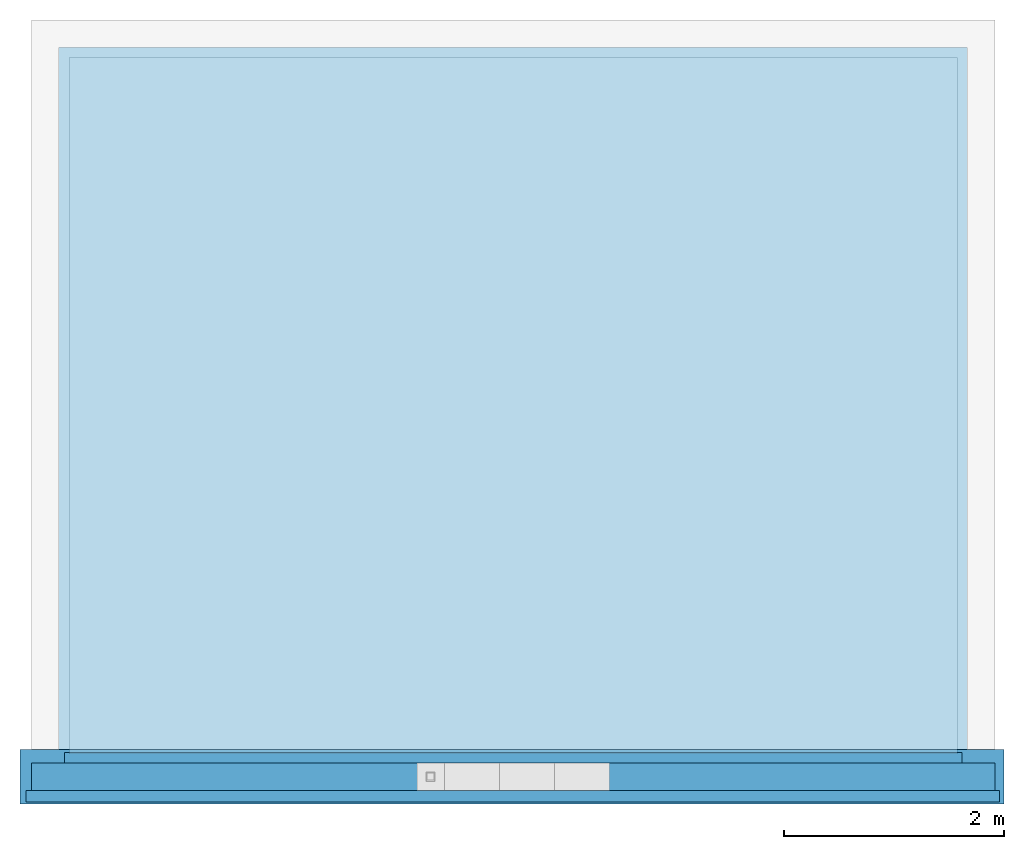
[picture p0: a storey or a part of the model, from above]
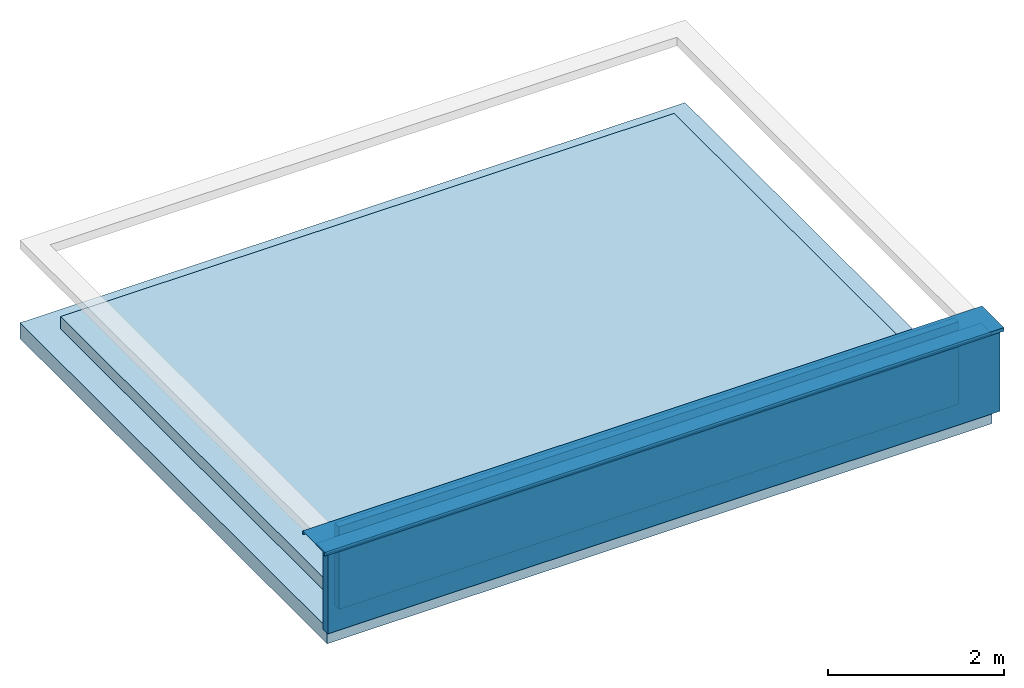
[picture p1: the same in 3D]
Properties of the parts of a building model (IFC4)

# File
Description: ViewDefinition [ReferenceView_V1.2], RevitIdentifiers [ContentGUID: d45b1106-0c7a-46e1-869b-c6a7bbcc7ea5, VersionGUID: 118b0530-1591-4ac2-8939-a10ffb714872, NumberOfSaves: 70], CoordinateReference [CoordinateBase: Internal Origin, ProjectSite: Internal], ExchangeRequirement [Architecture]
File name: 3dv__Detail__15__202, WS25, Roof, Anschluss Balkon _ Terrasse.ifc
Time: 2025-12-19T14:28:01+01:00
Written by: ODA SDAI 25.12
Made in: Autodesk - Revit 26.3.0.37 (ENU) - 26.4.1.0

# IfcSite, Default
RefLatitude: 45, 45, 37, 23925; RefLongitude: 21, 14, 26, 780090; RefElevation: 0 cm

# IfcBuildingStorey (10)
Name | LongName | Elevation (cm)
B2__ABOVE Slab | B2__ABOVE Slab | -612
B1__ABOVE Slab | B1__ABOVE Slab | -312
L00__ABOVE Slab | L00__ABOVE Slab | -12
L01__ABOVE Slab | L01__ABOVE Slab | 273
L02__ABOVE Slab | L02__ABOVE Slab | 558
L03__ABOVE Slab | L03__ABOVE Slab | 843
L04__ABOVE Slab | L04__ABOVE Slab | 1128
L05__ABOVE Slab | L05__ABOVE Slab | 1413
L06__ABOVE Slab | L06__ABOVE Slab | 1698
L07__ABOVE Slab | L07__ABOVE Slab | 1983

# IfcBeam: Structural Framing : wll__PARAPET CAP__Metal__sf : Wall Coping w/ H 50mm Nose, Standing Seam Profile
In: L03__ABOVE Slab
Type - PredefinedType: BEAM; Material: _SILL__Sill__Metal
Classification: A 4.4.1 Flashing-uri tabla faltuita (Uniformat)

# IfcCovering: Ceilings : Compound Ceiling : clg__INT COVERING__, GB 1.5cm__12.5(A) 3
In: L02__ABOVE Slab
Type - PredefinedType: CEILING
Classification: A 6.1.2.1 Plafoane gips-carton, placi cu cerinte standard (Uniformat); Material: _WLL & CLG FINISHES__Lime - CEM Plaster

# IfcOpeningElement (6)
PredefinedType: OPENING
Name | In
3 x Walls : Basic Wall : wll__INT FINISH__Spritzkork, Lime - CEM Plaster 2.4cm TRIQBRIQ | L02__ABOVE Slab | Classification: A 4.1.2.2 Tamplarii exterioare PVC (Uniformat)
Floor:flr__EXT ANCILLARY__Foam Glass 11.9cm__Parapet Cap, TriqBriq, RFa.1:41549196 | L03__ABOVE Slab
2 x Walls : Basic Wall : wll__EXT ENCLOSURE__Spritzkork, Wood Insulation 10.6cm__TriqBriq, FS.3 3 | L02__ABOVE Slab

# IfcSlab: Floors : Floor : flr__EXT ANCILLARY__Foam Glass 11.9cm__Parapet Cap, TriqBriq, RFa.1
In: L03__ABOVE Slab
Type - PredefinedType: FLOOR; Material: _FLAT ROOF LAYERS__WP Membrane (2), _FND LAYERS__Insulation__Foam Glass__Glapor, _FLAT ROOF LAYERS__Vapor Barrier__ProClima
Classification: A 3.7.1 Acoperisuri terasa (Uniformat)

# IfcSlab: Floors : Floor : flr__EXT ENCLOSURE__Balkon
In: L03__ABOVE Slab
Type - PredefinedType: FLOOR; Material: _FLR LAYERS__Screed, SL 0.5%__Semi-dry CEM, Rc ≥ 22.5 N/mm², _GREENERY__Subgrade__Earth, _GREENERY__Drainage & Storage Course__BauderGREEN DSE 20/1, _FLAT ROOF LAYERS__Filtering Fleece__Geotextile__BauderGREEN FV 125, _FLAT ROOF LAYERS__WP Protection__Fiber Mat__BauderGREEN FSM 600, _FLAT ROOF LAYERS__WP Membrane (2), _FND LAYERS__Insulation__Foam Glass__Glapor, _FLAT ROOF LAYERS__Vapor Barrier__ProClima
Classification: A 3.3.6 Sisteme verzi / terase innierbate (Uniformat)

# IfcSlab: Floors : Floor : flr__STRUCTURE__Wood CLT 22cm__TriqBriq, TW.5
In: L03__ABOVE Slab
Type - PredefinedType: FLOOR; Material: _STRUCTURE__Wood CLT
Classification: S 1.2 Plansee si acoperisuri terasa (Uniformat)

# IfcWall: Columns : wll_s__DECOUPLING BEAM__Rectangular__wp : Wood (2)
Type - PredefinedType: SOLIDWALL; Material: _STRUCTURE__Wood Solid
Classification: A 1.0.3 (Uniformat)
Name (Columns : wll_s__DECOUPLING BEAM__Rectangular__wp :...) | In
 Wood | L02__ABOVE Slab
 Wood | L03__ABOVE Slab

# IfcWall: Columns : wll_s__TIMBER BLOCK__Triqbriq, Full Width__wp1 : WS25 2 (22)
Type - PredefinedType: SOLIDWALL; Material: Miscellaneous__Timber Block__Triqbriq, Y
Classification: A 1.0.1 (Uniformat)
Name (Columns : wll_s__TIMBER BLOCK__Triqbriq, Full Width__wp1 :...) | In
10 x  WS25 2 | L02__ABOVE Slab
12 x  WS25 2 | L03__ABOVE Slab

# IfcWall: Columns : wll_s__TIMBER BLOCK__Triqbriq, Half Width__wp1 : WS25 2
In: L02__ABOVE Slab
Type - PredefinedType: SOLIDWALL; Material: Miscellaneous__Timber Block__Triqbriq, Y
Classification: A 1.0.1 (Uniformat)

# IfcWall: Walls : Basic Wall : wll__EXT ENCLOSURE__Spritzkork, Foam Glass 9.5cm__TriqBriq, FS.4
In: L03__ABOVE Slab
Type - PredefinedType: STANDARD; Material: _FCD FINISH__Spray-cork, _FLAT ROOF LAYERS__WP Membrane (2), _FND LAYERS__Insulation__Foam Glass__Glapor, _FLAT ROOF LAYERS__Vapor Barrier__ProClima
Classification: A 4.3.4.2.1 Pereti exteriori (Uniformat)

# IfcWall: Walls : Basic Wall : wll__EXT ENCLOSURE__Spritzkork, Wood Insulation 10.6cm__TriqBriq, FS.3 3 (2)
Type - PredefinedType: STANDARD; Material: _FCD FINISH__Spray-cork, Default Wall, _FCD LAYERS__Insulation__Wood-fiber__Steico
Classification: A 4.3.4.2.1 Pereti exteriori (Uniformat)
Name (Walls : Basic Wall :...) | In
 wll__EXT ENCLOSURE__Spritzkork, Wood Insulation 10.6cm__TriqBriq, FS.3 3 | L02__ABOVE Slab
 wll__EXT ENCLOSURE__Spritzkork, Wood Insulation 10.6cm__TriqBriq, FS.3 3 | L03__ABOVE Slab

# IfcWall: Walls : Basic Wall : wll__INT FINISH__Spritzkork, Lime - CEM Plaster 2.4cm TRIQBRIQ
In: L02__ABOVE Slab
Type - PredefinedType: STANDARD; Material: _WLL & CLG FINISHES__Lime - CEM Plaster, _FCD LAYERS__Insulation__EPS 120__Austrotherm EPS A120
Classification: A 7.1.1 Tencuieli umede (Uniformat)
